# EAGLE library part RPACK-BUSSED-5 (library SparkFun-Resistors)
BOURNS 4600X series thick-film SIP resistor packs Five resistors bussed to a single pin (denoted by dot). 0.2W / resistor datasheet SFE parts COM-10855 (330), COM-10856 (10K)

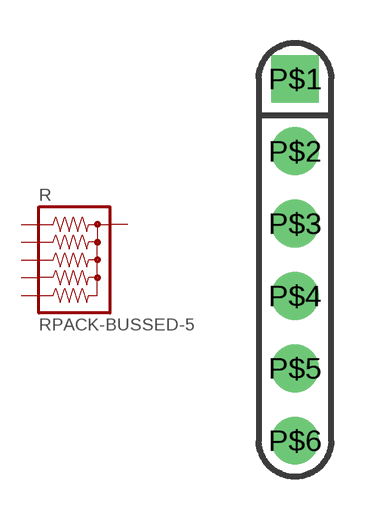
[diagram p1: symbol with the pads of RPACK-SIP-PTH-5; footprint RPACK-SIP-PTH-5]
Designator prefix R

## RPACK-BUSSED-5-SIP-PTH-5  [RPACK-SIP-PTH-5]
P$1  1  pas
P$2  2  pas
P$3  3  pas
P$4  4  pas
P$5  5  pas
P$6  6  pas

## Footprint RPACK-SIP-PTH-5 (pad centres in mm)
drill 0.8 pad 1.676 square: P$1 0,0
drill 0.8 pad 1.676: P$2 0,-2.54; P$3 0,-5.08; P$4 0,-7.62; P$5 0,-10.16; P$6 0,-12.7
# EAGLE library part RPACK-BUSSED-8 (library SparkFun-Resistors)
BOURNS 4600X/R series thick-film SIP resistor packs Height resistors bussed to a single pin (denoted by dot). datasheet SIMILAR TO: SFE parts COM-10855 (330), COM-10856 (10K)

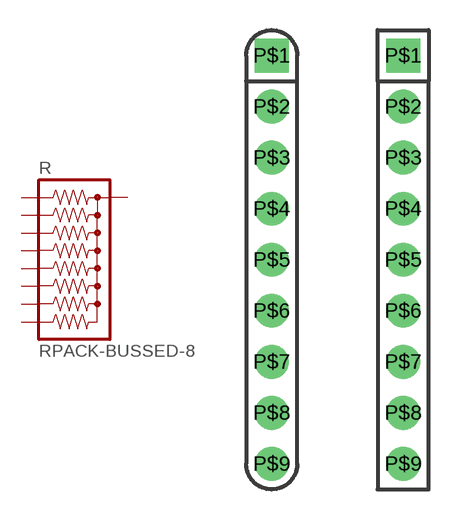
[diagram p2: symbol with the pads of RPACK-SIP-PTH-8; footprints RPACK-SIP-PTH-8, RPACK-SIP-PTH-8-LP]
Designator prefix R

## RPACK-BUSSED-8-SIP-PTH-8  [RPACK-SIP-PTH-8]
P$1  1  pas
P$2  2  pas
P$3  3  pas
P$4  4  pas
P$5  5  pas
P$6  6  pas
P$7  7  pas
P$8  8  pas
P$9  9  pas

## RPACK-BUSSED-8SIP-PTH-8-LP  [RPACK-SIP-PTH-8-LP]
Pads as for RPACK-SIP-PTH-8

## Footprint RPACK-SIP-PTH-8 (pad centres in mm)
drill 0.8 pad 1.676 square: P$1 0,0
drill 0.8 pad 1.676: P$2 0,-2.54; P$3 0,-5.08; P$4 0,-7.62; P$5 0,-10.16; P$6 0,-12.7; P$7 0,-15.24; P$8 0,-17.78; P$9 0,-20.32

## Footprint RPACK-SIP-PTH-8-LP (pad centres in mm)
drill 0.8 pad 1.676 square: P$1 0,0
drill 0.8 pad 1.676: P$2 0,-2.54; P$3 0,-5.08; P$4 0,-7.62; P$5 0,-10.16; P$6 0,-12.7; P$7 0,-15.24; P$8 0,-17.78; P$9 0,-20.32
